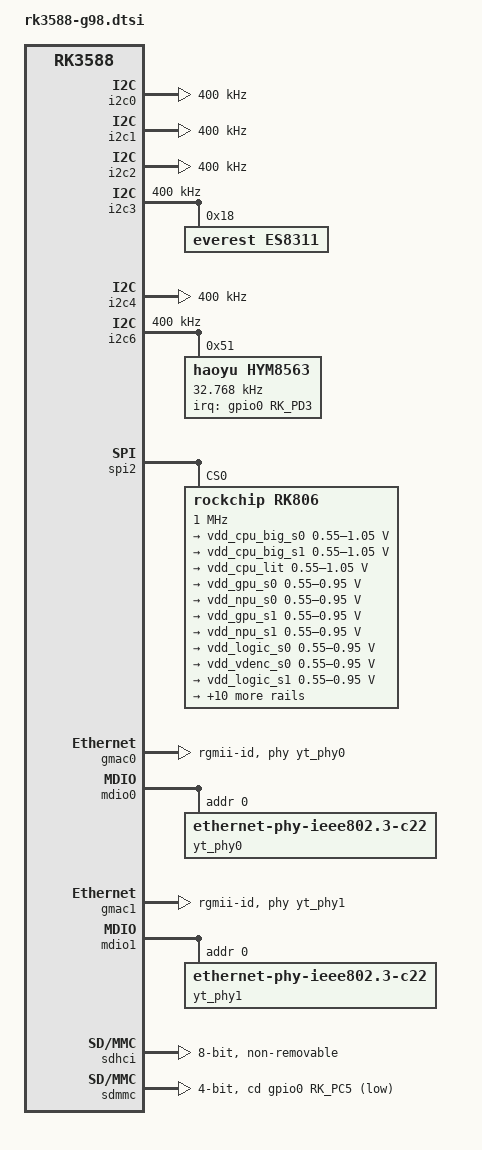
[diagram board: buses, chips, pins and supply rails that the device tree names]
// SPDX-License-Identifier: (GPL-2.0+ OR MIT)
/*
 * Copyright (c) 2026 stevenliuit
 *
 * Rockchip RK3588 G98 NVR Board — board-specific DTS overlay.
 * Include rk3588-g98-common.dtsi first, then rk3588.dtsi (from mainline).
 *
 * Notable features:
 *   - SPI-NOR (sfc @ 0xfeb10000) for U-Boot + kernel + DTBs
 *   - I2C3 ES8311 codec
 *   - I2C6 HYM8563 RTC
 *   - I2C0 RK806 PMIC (spmi-bus via spi2)
 *   - GMAC0 (0xfe1c0000) → YT9215S #0 (DSA switch, 4 LAN ports + 1 SGMII uplink)
 *   - GMAC1 (0xfe1b0000) → YT9215S #1 (DSA switch, 4 LAN ports + 1 SGMII uplink)
 *   - PCIe 2.0 x1 (4 lanes combined) → 2× RTL8125 2.5 GbE
 *   - PWM3 reserved (backlight not populated)
 *   - SARADC (vol-up key)
 *   - SD card + eMMC
 */

#include "dt-bindings/clock/rockchip,rk3588-cru.h"
#include "dt-bindings/power/rk3588-power.h"
#include "dt-bindings/reset/rockchip,rk3588-cru.h"

/* ============= I2C bus controllers ============= */
&i2c0 {
    status = "okay";
    pinctrl-names = "default";
    clock-frequency = <400000>;

    /* rk806 pmic bound via &spi2 (see spmi-bus below) */
};

&i2c1 {
    status = "okay";
    pinctrl-names = "default";
    clock-frequency = <400000>;
};

&i2c2 {
    status = "okay";
    pinctrl-names = "default";
    clock-frequency = <400000>;
};

&i2c3 {
    status = "okay";
    pinctrl-names = "default";
    clock-frequency = <400000>;

    es8311: es8311@18 {
        compatible = "everest,es8311";
        reg = <0x18>;
        pinctrl-names = "default";
        #sound-dai-cells = <0>;
        status = "okay";
    };
};

&i2c4 {
    status = "okay";
    pinctrl-names = "default";
    clock-frequency = <400000>;
};

&i2c6 {
    status = "okay";
    pinctrl-names = "default";
    clock-frequency = <400000>;

    hym8563: rtc@51 {
        compatible = "haoyu,hym8563";
        reg = <0x51>;
        #clock-cells = <0>;
        clock-frequency = <32768>;
        clock-output-names = "hym8563";
        pinctrl-names = "default";
        interrupt-parent = <&gpio0>;
        interrupts = <RK_PD3 IRQ_TYPE_LEVEL_LOW>;
        status = "okay";
    };
};

/* ============= SPI2 — used for RK806 PMIC over SPMI ============= */
&spi2 {
    status = "okay";
    pinctrl-names = "default";

    rk806: pmic@0 {
        compatible = "rockchip,rk806";
        reg = <0x0>;
        spi-max-frequency = <1000000>;
        spi-cpha;
        spi-cpol;

        pinctrl-names = "default";
        pinctrl-0 = <&pmic_pins>, <&rk806_dvs1_pins>, <&rk806_dvs2_pins>,
                <&rk806_dvs3_pins>;

        system-power-controller;

        #address-cells = <1>;
        #size-cells = <0>;

        vdd_cpu_big_s0: regulator@0 {
            reg = <0x0>;
            regulator-compatible = "rk806-buck1";
            regulator-name = "vdd_cpu_big_s0";
            regulator-min-microvolt = <550000>;
            regulator-max-microvolt = <1050000>;
            regulator-ramp-delay = <12500>;
            regulator-boot-on;
            regulator-always-on;
        };

        vdd_cpu_big_s1: regulator@1 {
            reg = <0x1>;
            regulator-compatible = "rk806-buck2";
            regulator-name = "vdd_cpu_big_s1";
            regulator-min-microvolt = <550000>;
            regulator-max-microvolt = <1050000>;
            regulator-ramp-delay = <12500>;
            regulator-boot-on;
            regulator-always-on;
        };

        vdd_cpu_lit: regulator@2 {
            reg = <0x2>;
            regulator-compatible = "rk806-buck3";
            regulator-name = "vdd_cpu_lit";
            regulator-min-microvolt = <550000>;
            regulator-max-microvolt = <1050000>;
            regulator-ramp-delay = <12500>;
            regulator-boot-on;
            regulator-always-on;
        };

        vdd_gpu_s0: regulator@3 {
            reg = <0x3>;
            regulator-compatible = "rk806-buck4";
            regulator-name = "vdd_gpu_s0";
            regulator-min-microvolt = <550000>;
            regulator-max-microvolt = <950000>;
            regulator-ramp-delay = <12500>;
            regulator-boot-on;
            regulator-always-on;
        };

        vdd_npu_s0: regulator@4 {
            reg = <0x4>;
            regulator-compatible = "rk806-buck5";
            regulator-name = "vdd_npu_s0";
            regulator-min-microvolt = <550000>;
            regulator-max-microvolt = <950000>;
            regulator-ramp-delay = <12500>;
            regulator-boot-on;
            regulator-always-on;
        };

        vdd_gpu_s1: regulator@5 {
            reg = <0x5>;
            regulator-compatible = "rk806-buck6";
            regulator-name = "vdd_gpu_s1";
            regulator-min-microvolt = <550000>;
            regulator-max-microvolt = <950000>;
            regulator-ramp-delay = <12500>;
            regulator-boot-on;
            regulator-always-on;
        };

        vdd_npu_s1: regulator@6 {
            reg = <0x6>;
            regulator-compatible = "rk806-buck7";
            regulator-name = "vdd_npu_s1";
            regulator-min-microvolt = <550000>;
            regulator-max-microvolt = <950000>;
            regulator-ramp-delay = <12500>;
            regulator-boot-on;
            regulator-always-on;
        };

        vdd_logic_s0: regulator@7 {
            reg = <0x7>;
            regulator-compatible = "rk806-buck8";
            regulator-name = "vdd_logic_s0";
            regulator-min-microvolt = <550000>;
            regulator-max-microvolt = <950000>;
            regulator-ramp-delay = <12500>;
            regulator-boot-on;
            regulator-always-on;
        };

        vdd_vdenc_s0: regulator@8 {
            reg = <0x8>;
            regulator-compatible = "rk806-buck9";
            regulator-name = "vdd_vdenc_s0";
            regulator-min-microvolt = <550000>;
            regulator-max-microvolt = <950000>;
            regulator-ramp-delay = <12500>;
            regulator-boot-on;
        };

        vdd_logic_s1: regulator@9 {
            reg = <0x9>;
            regulator-compatible = "rk806-buck10";
            regulator-name = "vdd_logic_s1";
            regulator-min-microvolt = <550000>;
            regulator-max-microvolt = <950000>;
            regulator-ramp-delay = <12500>;
            regulator-boot-on;
            regulator-always-on;
        };

        avcc_1v8_s0: regulator@a {
            reg = <0xa>;
            regulator-compatible = "rk806-ldo1";
            regulator-name = "avcc_1v8_s0";
            regulator-min-microvolt = <1800000>;
            regulator-max-microvolt = <1800000>;
            regulator-boot-on;
            regulator-always-on;
        };

        vdd1_ddr_s0: regulator@b {
            reg = <0xb>;
            regulator-compatible = "rk806-ldo2";
            regulator-name = "vdd1_ddr_s0";
            regulator-min-microvolt = <800000>;
            regulator-max-microvolt = <1200000>;
            regulator-boot-on;
            regulator-always-on;
        };

        vdd2_ddr_s0: regulator@c {
            reg = <0xc>;
            regulator-compatible = "rk806-ldo3";
            regulator-name = "vdd2_ddr_s0";
            regulator-min-microvolt = <800000>;
            regulator-max-microvolt = <1200000>;
            regulator-boot-on;
            regulator-always-on;
        };

        vcc1v8_s3: regulator@d {
            reg = <0xd>;
            regulator-compatible = "rk806-ldo4";
            regulator-name = "vcc1v8_s3";
            regulator-min-microvolt = <1800000>;
            regulator-max-microvolt = <1800000>;
            regulator-boot-on;
            regulator-always-on;
        };

        avdd_1v2_s0: regulator@e {
            reg = <0xe>;
            regulator-compatible = "rk806-ldo5";
            regulator-name = "avdd_1v2_s0";
            regulator-min-microvolt = <1200000>;
            regulator-max-microvolt = <1200000>;
            regulator-boot-on;
            regulator-always-on;
        };

        vdd1_ddr_pll_s0: regulator@f {
            reg = <0xf>;
            regulator-compatible = "rk806-ldo6";
            regulator-name = "vdd1_ddr_pll_s0";
            regulator-min-microvolt = <800000>;
            regulator-max-microvolt = <1200000>;
            regulator-boot-on;
            regulator-always-on;
        };

        vcc_2v0_s3: regulator@10 {
            reg = <0x10>;
            regulator-compatible = "rk806-ldo7";
            regulator-name = "vcc_2v0_s3";
            regulator-min-microvolt = <2000000>;
            regulator-max-microvolt = <2000000>;
            regulator-boot-on;
            regulator-always-on;
        };

        vdd0_nldo_s3: regulator@11 {
            reg = <0x11>;
            regulator-compatible = "rk806-ldo8";
            regulator-name = "vdd0_nldo_s3";
            regulator-min-microvolt = <800000>;
            regulator-max-microvolt = <1200000>;
            regulator-boot-on;
            regulator-always-on;
        };

        vcc1v2_s0: regulator@12 {
            reg = <0x12>;
            regulator-compatible = "rk806-ldo9";
            regulator-name = "vcc1v2_s0";
            regulator-min-microvolt = <1200000>;
            regulator-max-microvolt = <1200000>;
            regulator-boot-on;
            regulator-always-on;
        };

        avcc_1v8_s2: regulator@13 {
            reg = <0x13>;
            regulator-compatible = "rk806-ldo10";
            regulator-name = "avcc_1v8_s2";
            regulator-min-microvolt = <1800000>;
            regulator-max-microvolt = <1800000>;
            regulator-boot-on;
        };
    };
};

/* ============= GMAC0 (0xfe1c0000) → YT9215S #0 ============= */
&gmac0 {
    status = "okay";
    pinctrl-names = "default";
    clock_in_out = "output";
    rx_delay = <0x30>;
    tx_delay = <0x10>;
    phy-mode = "rgmii-id";
    phy-handle = <&yt_phy0>;
    assigned-
};

&mdio0 {
    status = "okay";

    /* YT9215S #0 — motorcomm,yt9215 DSA switch
     * 5 ports: port 0..3 = external LAN1..LAN4 (1000BASE-T),
     *          port 4   = SGMII uplink to GMAC0.
     * The DSA switch nodes (ytgsw0, ytgsw1) are declared in the main file.
     * mdio bus to internal PHYs of yt9215s is routed via the switch.
     */
    yt_phy0: yt-phy0 {
        reg = <0>;
        compatible = "ethernet-phy-ieee802.3-c22";
    };
};

/* ============= GMAC1 (0xfe1b0000) → YT9215S #1 ============= */
&gmac1 {
    status = "okay";
    pinctrl-names = "default";
    clock_in_out = "output";
    rx_delay = <0x30>;
    tx_delay = <0x10>;
    phy-mode = "rgmii-id";
    phy-handle = <&yt_phy1>;
    assigned-
};

&mdio1 {
    status = "okay";

    yt_phy1: yt-phy1 {
        reg = <0>;
        compatible = "ethernet-phy-ieee802.3-c22";
    };
};

/* ============= YT9215S DSA switch nodes ============= */
/* ============= SPI-NOR (sfc @ 0xfeb10000) ============= */
/* ============= eMMC (sdhci @ 0xfe2e0000) ============= */
&sdhci {
    status = "okay";
    bus-width = <8>;
    non-removable;
    rockchip,default-sample-phase = <0x3>;
    rockchip,txclk-tapnum = <0x8>;
    mmc-ddr-1_8v;
    mmc-hs400-1_8v;
    mmc-hs400-enhanced-strobe;
    pinctrl-0 = <&emmc_bus8>, <&emmc_clk>, <&emmc_cmd>, <&emmc_data>;
    pinctrl-names = "default";
};

/* ============= SD card (sdmmc @ 0xfe310000) ============= */
&sdmmc {
    status = "okay";
    bus-width = <4>;
    cap-sd-highspeed;
    cd-gpios = <&gpio0 RK_PC5 GPIO_ACTIVE_LOW>;
    disable-wp;
    pinctrl-0 = <&sdmmc_bus4>, <&sdmmc_clk>, <&sdmmc_cmd>, <&sdmmc_det>;
    pinctrl-names = "default";
};

/* ============= PCIe 2.0 (RTL8125 #0 + #1) ============= */
/* PCIe 3.0 — reserved (not used on G98) */
/* ============= SARADC ============= */
/* ============= I2S / Sound ============= */
/* ============= HDMI TX0 — disabled (no HDMI connector on G98) ============= */
